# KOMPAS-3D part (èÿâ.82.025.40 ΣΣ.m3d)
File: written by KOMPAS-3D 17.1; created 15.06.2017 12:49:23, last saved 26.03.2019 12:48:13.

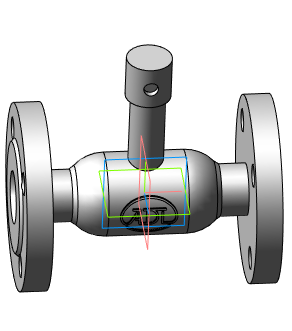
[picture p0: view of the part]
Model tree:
1. Операция без истории:2  (labels: Сталь 20  ГОСТ 1050-88)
